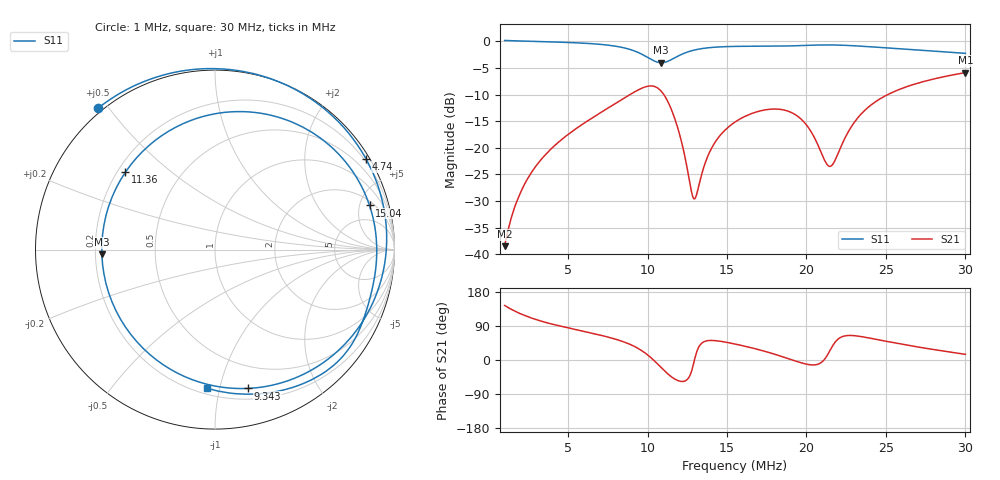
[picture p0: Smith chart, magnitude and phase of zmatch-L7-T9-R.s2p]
# HZ S RI R 50
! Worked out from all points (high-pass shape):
!   505 points, 1 MHz to 30 MHz, reference 50 ohm
!   highest |S21| = -5.84 dB at 30 MHz (marker M1); lowest = -38.5 dB at 1 MHz (marker M2)
!   |S21| within 3 dB of the highest: 9.592 MHz to 10.68 MHz (1.085 MHz wide, 10.7 % of centre); 25.99 MHz to end of sweep
!   lowest |S11| = -4.0 dB at 10.84 MHz (marker M3), VSWR 4.42, Z = 11.3 - j0.963 ohm
!   |S11| at or under -10 dB: nowhere
!   S12 and S22 are empty: the file has one direction only
!   S11 on the Smith chart (normalised r, x): 1 MHz: -0.01, +0.47; 4.74 MHz: 0.13, +3.60; 9.343 MHz: 0.29, -1.22; 11.36 MHz: 0.23, +0.35; 15.04 MHz: 2.48, +6.16; 30 MHz: 0.24, -0.91
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1000000  -0.6526 0.7866  -0.00964 0.00702  0 0  0 0
2438500  0.1324 0.9967  -0.0212 0.0465  0 0  0 0
3531760  0.5637 0.8197  -0.0144 0.0839  0 0  0 0
4740100  0.8413 0.5056  0.00612 0.1247  0 0  0 0
5833360  0.9481 0.1843  0.037 0.1599  0 0  0 0
7847260  0.7954 -0.4408  0.14 0.2122  0 0  0 0
9343300  0.1843 -0.7734  0.2939 0.1831  0 0  0 0
1.003378e7  -0.2886 -0.6415  0.3714 0.081  0 0  0 0
1.066672e7  -0.6076 -0.1883  0.3541 -0.0761  0 0  0 0
1.083934e7  -0.6305 -0.0256  0.3236 -0.1141  0 0  0 0
1.13572e7  -0.4991 0.4314  0.1971 -0.1637  0 0  0 0
1.204768e7  -0.062 0.743  0.0715 -0.1062  0 0  0 0
1.291078e7  0.4192 0.7144  0.033 -0.00384  0 0  0 0
1.39465e7  0.728 0.4879  0.0585 0.0737  0 0  0 0
1.503976e7  0.861 0.2459  0.1074 0.1115  0 0  0 0
1.550008e7  0.885 0.1562  0.1296 0.1175  0 0  0 0
1.837708e7  0.8666 -0.2578  0.2263 0.0408  0 0  0 0
2.033344e7  0.7937 -0.4698  0.1348 -0.0311  0 0  0 0
2.154178e7  0.713 -0.5937  0.0585 0.0336  0 0  0 0
2.321044e7  0.5589 -0.7145  0.0857 0.1699  0 0  0 0
2.51668e7  0.3716 -0.7844  0.2133 0.2381  0 0  0 0
3.000016e7  -0.047 -0.7718  0.4929 0.1318  0 0  0 0
